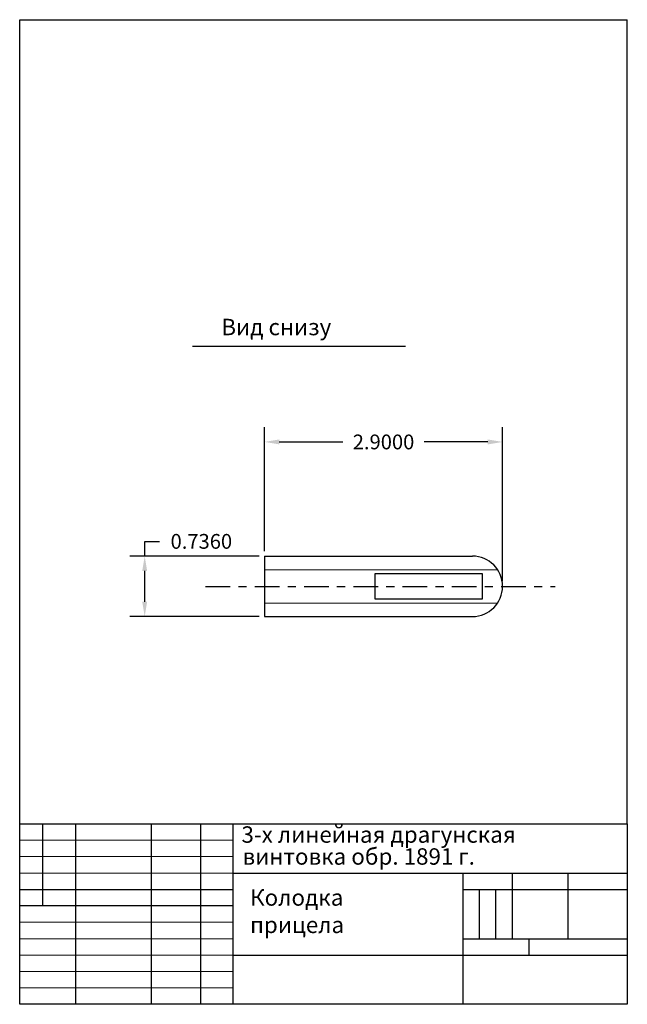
# Model space of a CAD drawing. Units: inches. Extents: x -3 to 4.4, y -5.1 to 6.9.
import ezdxf

# ---------------------------------------------------------------- set-up
doc = ezdxf.new("R2010")
doc.units = ezdxf.units.IN
doc.header["$LTSCALE"] = 0.1
doc.header["$MEASUREMENT"] = 0
doc.linetypes.add('ACAD_ISO10W100', pattern=[18, 12, -3, 0, -3])
doc.dimstyles.get("Standard").update_dxf_attribs({"dimtxt": 0.18, "dimasz": 0.18, "dimexe": 0.18, "dimexo": 0.0625, "dimgap": 0.09, "dimtad": 0, "dimtih": 1, "dimtoh": 1, "dimdec": 4, "dimzin": 0, "dimdsep": 46, "dimtxsty": 'Standard', "dimcen": 0.09, "dimadec": 0, "dimazin": 0, "dimtfac": 1, "dimtdec": 4, "dimtofl": 0, "dimtmove": 0, "dimatfit": 3, "dimfxl": 0, "dimtolj": 1, "dimtzin": 0, "dimarcsym": 0})

# ---------------------------------------------------------------- blocks, each defined once
blk = doc.blocks.new('*D3')
at = {"color": 0, "lineweight": -2, "ltscale": 0.25}
for p, q in [((0, 0.43), (0, 1.94)), ((2.9, 0.062), (2.9, 1.94)), ((0.18, 1.76), (0.955, 1.76)), ((2.72, 1.76), (1.945, 1.76))]:
    blk.add_line(p, q, dxfattribs=at)
at = {"color": 0, "lineweight": 25, "ltscale": 0.25}
for points in [[(0.18, 1.79), (0.18, 1.73), (0, 1.76)], [(2.72, 1.79), (2.72, 1.73), (2.9, 1.76)]]:
    blk.add_solid(points, dxfattribs=at)
at = {"layer": 'Defpoints', "color": 0, "lineweight": 25, "ltscale": 0.25}
for p in [(2.9, 1.76), (0, 0.368), (2.9, 0)]:
    blk.add_point(p, dxfattribs=at)
at = {"color": 0, "lineweight": 25, "ltscale": 0.25, "insert": (1.45, 1.76), "char_height": 0.18, "attachment_point": 5}
blk.add_mtext('\\A1;2.9000', dxfattribs=at)
blk = doc.blocks.new('*D4')
at = {"color": 0, "lineweight": -2, "ltscale": 0.25}
for p, q in [((-1.459, 0.368), (-1.459, 0.548)), ((-1.459, 0.548), (-1.279, 0.548)), ((-0.063, 0.368), (-1.639, 0.368)), ((-1.459, -0.188), (-1.459, 0.188)), ((-0.063, -0.368), (-1.639, -0.368))]:
    blk.add_line(p, q, dxfattribs=at)
at = {"color": 0, "lineweight": 25, "ltscale": 0.25}
for points in [[(-1.489, 0.188), (-1.429, 0.188), (-1.459, 0.368)], [(-1.489, -0.188), (-1.429, -0.188), (-1.459, -0.368)]]:
    blk.add_solid(points, dxfattribs=at)
at = {"layer": 'Defpoints', "color": 0, "lineweight": 25, "ltscale": 0.25}
for p in [(-1.459, 0.368), (0, 0.368), (0, -0.368)]:
    blk.add_point(p, dxfattribs=at)
at = {"color": 0, "lineweight": 25, "ltscale": 0.25, "insert": (-0.769, 0.548), "char_height": 0.18, "attachment_point": 5}
blk.add_mtext('\\A1;0.7360', dxfattribs=at)
blk = doc.blocks.new('ramka')
for p, q in [((0, 0), (0, 55)), ((0, 55), (185, 55)), ((65, 0), (65, 55)), ((185, 55), (185, 0)), ((185, 0), (0, 0))]:
    blk.add_line(p, q)
at = {"lineweight": 25}
for p, q in [((0, 0), (0, 55)), ((0, 55), (185, 55)), ((7, 30), (7, 55)), ((17, 55), (17, 0)), ((40, 55), (40, 0)), ((55, 55), (55, 0)), ((65, 0), (65, 55)), ((185, 55), (185, 0)), ((65, 40), (185, 40)), ((135, 0), (135, 40)), ((150, 35), (150, 40)), ((167, 20), (167, 40)), ((0, 35), (65, 35)), ((135, 35), (185, 35)), ((140, 20), (140, 35)), ((145, 20), (145, 35)), ((150, 20), (150, 35)), ((65, 30), (0, 30)), ((135, 20), (185, 20)), ((155, 20), (155, 15)), ((65, 15), (185, 15)), ((185, 0), (0, 0))]:
    blk.add_line(p, q, dxfattribs=at)
at = {"lineweight": 9}
for p, q in [((65, 50), (0, 50)), ((65, 45), (0, 45)), ((65, 40), (0, 40)), ((65, 25), (0, 25)), ((65, 20), (0, 20)), ((65, 15), (0, 15)), ((65, 10), (0, 10)), ((65, 5), (0, 5))]:
    blk.add_line(p, q, dxfattribs=at)

msp = doc.modelspace()

# ---------------------------------------------------------------- linework, layer by layer
at = {"color": 7, "lineweight": 25, "ltscale": 0.25}
for p, q in [((-2.98121, -2.89396), (-2.98121, 6.90604)), ((-2.98121, 6.90604), (4.41879, 6.90604)), ((4.41879, -2.89396), (4.41879, 6.90604))]:
    msp.add_line(p, q, dxfattribs=at)
at = {"color": 3, "lineweight": 25, "ltscale": 0.25}
msp.add_line((-0.87503, 2.92618), (1.71823, 2.92618), dxfattribs=at)
at = {"color": 7, "lineweight": 25, "ltscale": 0.7}
for p, q in [((0, 0.368), (0, -0.368)), ((0, 0.368), (2.532, 0.368)), ((0, 0.2058), (2.83949, 0.20218)), ((1.35, -0.158), (1.35, 0.158)), ((1.35, 0.158), (2.65, 0.158)), ((2.65, 0.158), (2.65, -0.158)), ((0, -0.2058), (2.83949, -0.20218)), ((2.65, -0.158), (1.35, -0.158)), ((0, -0.368), (2.53936, -0.368))]:
    msp.add_line(p, q, dxfattribs=at)
at = {"color": 1, "linetype": 'ACAD_ISO10W100', "lineweight": 25, "ltscale": 0.25}
msp.add_line((-0.7174, 0), (3.54068, 0), dxfattribs=at)
at = {"color": 7, "lineweight": 25, "ltscale": 0.7}
msp.add_arc((2.532, 0), 0.368, 270, 90, dxfattribs=at)

# ---------------------------------------------------------------- block references
at = {"color": 3, "lineweight": 25, "ltscale": 0.25, "xscale": 0.04, "yscale": 0.04}
msp.add_blockref('ramka', (-2.98121, -5.09396), dxfattribs=at)

# ---------------------------------------------------------------- texts
at = {"color": 3, "lineweight": 25, "ltscale": 0.25}
msp.add_text('Вид снизу', height=0.2, dxfattribs=at).set_placement((-0.52568, 3.06041))
at = {"color": 7, "lineweight": 25, "ltscale": 0.25}
for s, p in [('3-х линейная драгунская', (-0.28033, -3.1251)), ('винтовка обр. 1891 г.', (-0.26804, -3.39228)), ('Колодка', (-0.17537, -3.89216)), ('прицела', (-0.17537, -4.2255))]:
    msp.add_text(s, height=0.2, dxfattribs=at).set_placement(p)

# ---------------------------------------------------------------- dimensions: what is measured, and where the dimension line sits
at = {"color": 3, "lineweight": 25, "ltscale": 0.25}
dim = msp.add_linear_dim(base=(2.9, 1.75954), p1=(0, 0.368), p2=(2.9, 0), dimstyle='Standard', dxfattribs=at)
dim.commit()
dim.dimension.update_dxf_attribs({"geometry": '*D3', "text_midpoint": (1.45, 1.75954)})
dim = msp.add_linear_dim(base=(-1.45897, 0.368), p1=(0, -0.368), p2=(0, 0.368), angle=90, dimstyle='Standard', dxfattribs=at)
dim.commit()
dim.dimension.update_dxf_attribs({"geometry": '*D4', "text_midpoint": (-0.76897, 0.548)})

doc.saveas('drawing.dxf')
